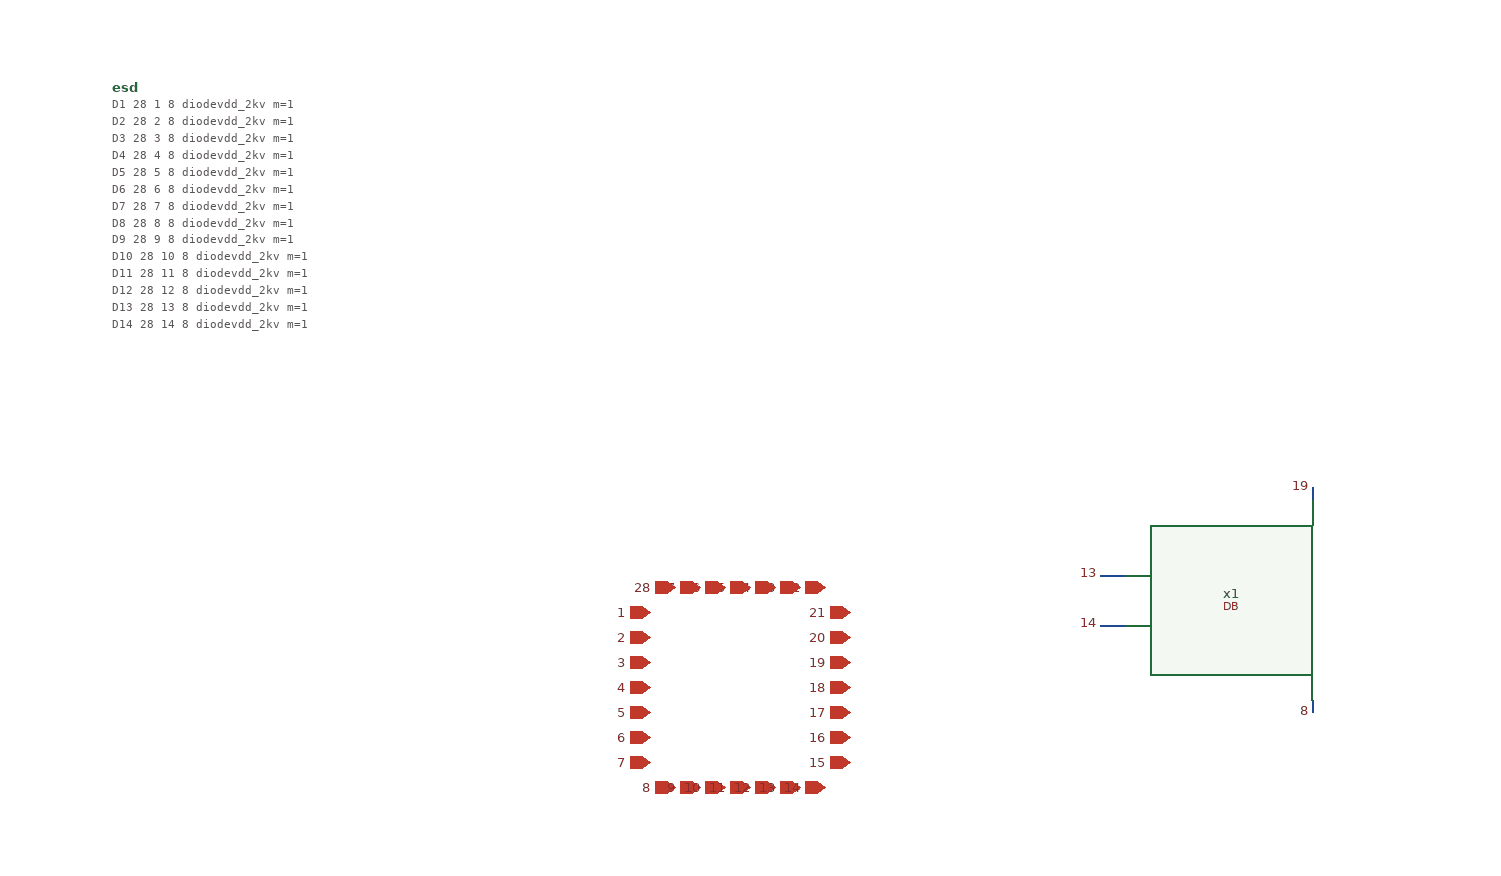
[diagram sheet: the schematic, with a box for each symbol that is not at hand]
v {xschem version=3.4.5 file_version=1.2
}
G {}
K {}
V {}
S {}
E {}
N 200 -30 200 -20 {
lab=8}
N 200 -200 200 -190 {
lab=19}
N 30 -130 50 -130 {
lab=13}
N 30 -90 50 -90 {
lab=14}
C {iopin.sym} -330 -100 2 0 {name=p8 lab=1}
C {iopin.sym} -330 -80 2 0 {name=p9 lab=2}
C {iopin.sym} -330 -60 2 0 {name=p10 lab=3}
C {iopin.sym} -330 -40 2 0 {name=p11 lab=4}
C {iopin.sym} -330 -20 2 0 {name=p12 lab=5}
C {iopin.sym} -330 0 2 0 {name=p13 lab=6}
C {iopin.sym} -330 20 2 0 {name=p14 lab=7}
C {iopin.sym} -310 40 1 0 {name=p15 lab=8}
C {iopin.sym} -290 40 1 0 {name=p16 lab=9}
C {iopin.sym} -270 40 1 0 {name=p17 lab=10}
C {iopin.sym} -250 40 1 0 {name=p18 lab=11}
C {iopin.sym} -230 40 1 0 {name=p19 lab=12}
C {iopin.sym} -210 40 1 0 {name=p20 lab=13}
C {iopin.sym} -190 40 1 0 {name=p21 lab=14}
C {iopin.sym} -170 20 0 0 {name=p22 lab=15}
C {iopin.sym} -170 0 0 0 {name=p23 lab=16}
C {iopin.sym} -170 -20 0 0 {name=p24 lab=17}
C {iopin.sym} -170 -40 0 0 {name=p25 lab=18}
C {iopin.sym} -170 -60 0 0 {name=p26 lab=19}
C {iopin.sym} -170 -80 0 0 {name=p27 lab=20}
C {iopin.sym} -170 -100 0 0 {name=p28 lab=21}
C {iopin.sym} -190 -120 3 0 {name=p29 lab=22}
C {iopin.sym} -210 -120 3 0 {name=p30 lab=23}
C {iopin.sym} -230 -120 3 0 {name=p31 lab=24}
C {iopin.sym} -250 -120 3 0 {name=p32 lab=25}
C {iopin.sym} -270 -120 3 0 {name=p33 lab=26}
C {iopin.sym} -290 -120 3 0 {name=p34 lab=27}
C {iopin.sym} -310 -120 3 0 {name=p35 lab=28}
C {code_shown.sym} -760 -520 0 0 {name=esd only_toplevel=false value="
D1 28 1 8 diodevdd_2kv m=1
D2 28 2 8 diodevdd_2kv m=1
D3 28 3 8 diodevdd_2kv m=1
D4 28 4 8 diodevdd_2kv m=1
D5 28 5 8 diodevdd_2kv m=1
D6 28 6 8 diodevdd_2kv m=1
D7 28 7 8 diodevdd_2kv m=1
D8 28 8 8 diodevdd_2kv m=1
D9 28 9 8 diodevdd_2kv m=1
D10 28 10 8 diodevdd_2kv m=1
D11 28 11 8 diodevdd_2kv m=1
D12 28 12 8 diodevdd_2kv m=1
D13 28 13 8 diodevdd_2kv m=1
D14 28 14 8 diodevdd_2kv m=1
D15 28 15 8 diodevdd_2kv m=1
D16 28 16 8 diodevdd_2kv m=1
D17 28 17 8 diodevdd_2kv m=1
D18 28 18 8 diodevdd_2kv m=1
D19 28 19 8 diodevdd_2kv m=1
D20 28 20 8 diodevdd_2kv m=1
D21 28 21 8 diodevdd_2kv m=1
D22 28 22 8 diodevdd_2kv m=1
D23 28 23 8 diodevdd_2kv m=1
D24 28 24 8 diodevdd_2kv m=1
D25 28 25 8 diodevdd_2kv m=1
D26 28 26 8 diodevdd_2kv m=1
D27 28 27 8 diodevdd_2kv m=1
D28 28 28 8 diodevdd_2kv m=1

D29 28 1 8 diodevss_2kv m=1
D30 28 2 8 diodevss_2kv m=1
D31 28 3 8 diodevss_2kv m=1
D32 28 4 8 diodevss_2kv m=1
D33 28 5 8 diodevss_2kv m=1
D34 28 6 8 diodevss_2kv m=1
D35 28 7 8 diodevss_2kv m=1
D36 28 8 8 diodevss_2kv m=1
D37 28 9 8 diodevss_2kv m=1
D38 28 10 8 diodevss_2kv m=1
D39 28 11 8 diodevss_2kv m=1
D40 28 12 8 diodevss_2kv m=1
D41 28 13 8 diodevss_2kv m=1
D42 28 14 8 diodevss_2kv m=1
D43 28 15 8 diodevss_2kv m=1
D44 28 16 8 diodevss_2kv m=1
D45 28 17 8 diodevss_2kv m=1
D46 28 18 8 diodevss_2kv m=1
D47 28 19 8 diodevss_2kv m=1
D48 28 20 8 diodevss_2kv m=1
D49 28 21 8 diodevss_2kv m=1
D50 28 22 8 diodevss_2kv m=1
D51 28 23 8 diodevss_2kv m=1
D52 28 24 8 diodevss_2kv m=1
D53 28 25 8 diodevss_2kv m=1
D54 28 26 8 diodevss_2kv m=1
D55 28 27 8 diodevss_2kv m=1
D56 28 28 8 diodevss_2kv m=1
"}
C {/workspaces/usm-vlsi-tools/shared_xserver/TORepo_IHPNov2024_TDBuck/design_data/xschem/Digital_Block/DB.sym} 200 -110 0 0 {name=x1}
C {lab_pin.sym} 200 -20 0 0 {name=p1 sig_type=std_logic lab=8}
C {lab_pin.sym} 200 -200 0 0 {name=p2 sig_type=std_logic lab=19}
C {lab_pin.sym} 30 -130 0 0 {name=p3 sig_type=std_logic lab=13}
C {lab_pin.sym} 30 -90 0 0 {name=p4 sig_type=std_logic lab=14}
